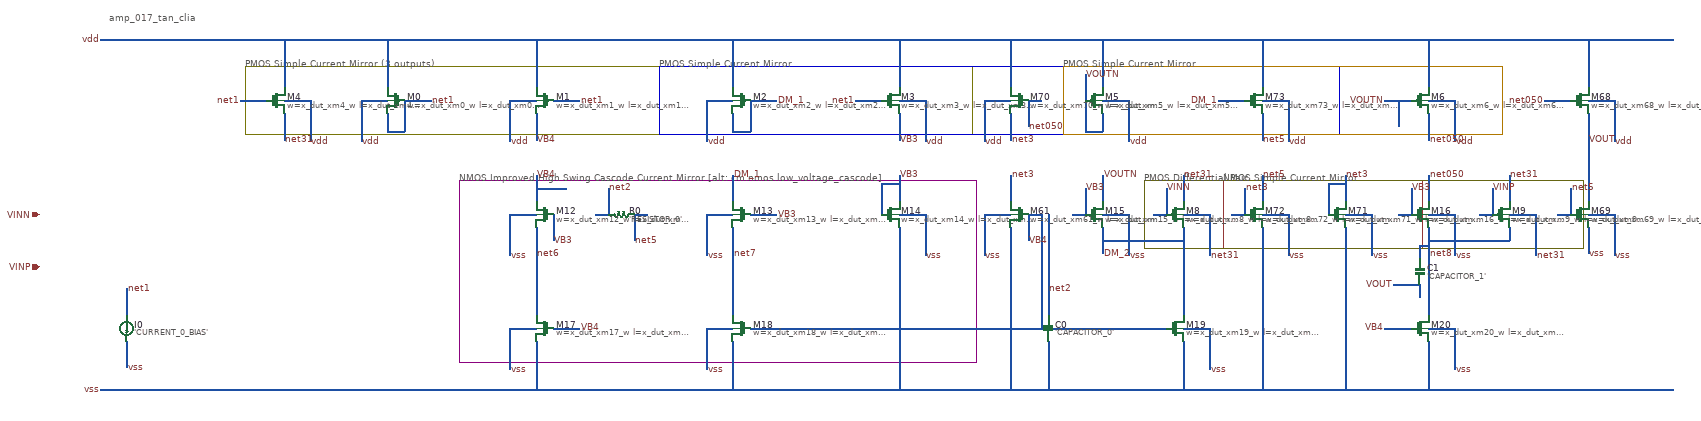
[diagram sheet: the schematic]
v {xschem version=3.4.6 file_version=1.2}
G {}
K {}
V {}
S {}
E {}
T {amp_017_tan_clia} -1755 -200 0 0 0.4 0.4 {}
C {devices/capa_np.sym} 390 520 0 0 {name=C0 value='CAPACITOR_0'}
C {devices/capa_np.sym} 1240 390 0 0 {name=C1 value='CAPACITOR_1'}
C {devices/isource_np.sym} -1715 520 0 0 {name=I0 value='CURRENT_0_BIAS'}
C {devices/res_np.sym} -585 260 1 0 {name=R0 value='RESISTOR_0'}
C {devices/sg13_lv_pmos_np.sym} -1100 0 0 1 {name=M0 model=sg13_lv_pmos spiceprefix=X w=x_dut_xm0_w l=x_dut_xm0_l m=x_dut_xm0_m}
C {devices/sg13_lv_pmos_np.sym} -760 0 0 1 {name=M1 model=sg13_lv_pmos spiceprefix=X w=x_dut_xm1_w l=x_dut_xm1_l m=x_dut_xm1_m}
C {devices/sg13_lv_nmos_np.sym} -760 260 0 1 {name=M12 model=sg13_lv_nmos spiceprefix=X w=x_dut_xm12_w l=x_dut_xm12_l m=x_dut_xm12_m}
C {devices/sg13_lv_nmos_np.sym} -310 260 0 1 {name=M13 model=sg13_lv_nmos spiceprefix=X w=x_dut_xm13_w l=x_dut_xm13_l m=x_dut_xm13_m}
C {devices/sg13_lv_nmos_np.sym} 30 260 0 0 {name=M14 model=sg13_lv_nmos spiceprefix=X w=x_dut_xm14_w l=x_dut_xm14_l m=x_dut_xm14_m}
C {devices/sg13_lv_nmos_np.sym} 495 260 0 0 {name=M15 model=sg13_lv_nmos spiceprefix=X w=x_dut_xm15_w l=x_dut_xm15_l m=x_dut_xm15_m}
C {devices/sg13_lv_nmos_np.sym} 1240 260 0 0 {name=M16 model=sg13_lv_nmos spiceprefix=X w=x_dut_xm16_w l=x_dut_xm16_l m=x_dut_xm16_m}
C {devices/sg13_lv_nmos_np.sym} -760 520 0 1 {name=M17 model=sg13_lv_nmos spiceprefix=X w=x_dut_xm17_w l=x_dut_xm17_l m=x_dut_xm17_m}
C {devices/sg13_lv_nmos_np.sym} -310 520 0 1 {name=M18 model=sg13_lv_nmos spiceprefix=X w=x_dut_xm18_w l=x_dut_xm18_l m=x_dut_xm18_m}
C {devices/sg13_lv_nmos_np.sym} 680 520 0 0 {name=M19 model=sg13_lv_nmos spiceprefix=X w=x_dut_xm19_w l=x_dut_xm19_l m=x_dut_xm19_m}
C {devices/sg13_lv_pmos_np.sym} -310 0 0 1 {name=M2 model=sg13_lv_pmos spiceprefix=X w=x_dut_xm2_w l=x_dut_xm2_l m=x_dut_xm2_m}
C {devices/sg13_lv_nmos_np.sym} 1240 520 0 0 {name=M20 model=sg13_lv_nmos spiceprefix=X w=x_dut_xm20_w l=x_dut_xm20_l m=x_dut_xm20_m}
C {devices/sg13_lv_pmos_np.sym} 30 0 0 0 {name=M3 model=sg13_lv_pmos spiceprefix=X w=x_dut_xm3_w l=x_dut_xm3_l m=x_dut_xm3_m}
C {devices/sg13_lv_pmos_np.sym} -1375 0 0 0 {name=M4 model=sg13_lv_pmos spiceprefix=X w=x_dut_xm4_w l=x_dut_xm4_l m=x_dut_xm4_m}
C {devices/sg13_lv_pmos_np.sym} 495 0 0 0 {name=M5 model=sg13_lv_pmos spiceprefix=X w=x_dut_xm5_w l=x_dut_xm5_l m=x_dut_xm5_m}
C {devices/sg13_lv_pmos_np.sym} 1240 0 0 0 {name=M6 model=sg13_lv_pmos spiceprefix=X w=x_dut_xm6_w l=x_dut_xm6_l m=x_dut_xm6_m}
C {devices/sg13_lv_nmos_np.sym} 325 260 0 1 {name=M61 model=sg13_lv_nmos spiceprefix=X w=x_dut_xm61_w l=x_dut_xm61_l m=x_dut_xm61_m}
C {devices/sg13_lv_pmos_np.sym} 1605 0 0 0 {name=M68 model=sg13_lv_pmos spiceprefix=X w=x_dut_xm68_w l=x_dut_xm68_l m=x_dut_xm68_m}
C {devices/sg13_lv_nmos_np.sym} 1605 260 0 0 {name=M69 model=sg13_lv_nmos spiceprefix=X w=x_dut_xm69_w l=x_dut_xm69_l m=x_dut_xm69_m}
C {devices/sg13_lv_pmos_np.sym} 325 0 0 1 {name=M70 model=sg13_lv_pmos spiceprefix=X w=x_dut_xm70_w l=x_dut_xm70_l m=x_dut_xm70_m}
C {devices/sg13_lv_nmos_np.sym} 1050 260 0 0 {name=M71 model=sg13_lv_nmos spiceprefix=X w=x_dut_xm71_w l=x_dut_xm71_l m=x_dut_xm71_m}
C {devices/sg13_lv_nmos_np.sym} 860 260 0 0 {name=M72 model=sg13_lv_nmos spiceprefix=X w=x_dut_xm72_w l=x_dut_xm72_l m=x_dut_xm72_m}
C {devices/sg13_lv_pmos_np.sym} 860 0 0 0 {name=M73 model=sg13_lv_pmos spiceprefix=X w=x_dut_xm73_w l=x_dut_xm73_l m=x_dut_xm73_m}
C {devices/sg13_lv_pmos_np.sym} 680 260 0 0 {name=M8 model=sg13_lv_pmos spiceprefix=X w=x_dut_xm8_w l=x_dut_xm8_l m=x_dut_xm8_m}
C {devices/sg13_lv_pmos_np.sym} 1425 260 0 0 {name=M9 model=sg13_lv_pmos spiceprefix=X w=x_dut_xm9_w l=x_dut_xm9_l m=x_dut_xm9_m}
N -1715 430 -1715 490 {}
N -1715 550 -1715 610 {}
N -1355 -140 -1355 -30 {}
N -1355 30 -1355 90 {}
N -1295 0 -1295 94 {}
N -1180 0 -1180 94 {}
N -1120 -140 -1120 -30 {}
N -1120 30 -1120 70 {}
N -1080 0 -1080 70 {}
N -840 0 -840 94 {}
N -840 260 -840 354 {}
N -840 520 -840 614 {}
N -780 -140 -780 -30 {}
N -780 30 -780 90 {}
N -780 170 -780 230 {}
N -780 290 -780 490 {}
N -780 550 -780 660 {}
N -740 260 -740 320 {}
N -615 200 -615 260 {}
N -555 260 -555 320 {}
N -390 0 -390 94 {}
N -390 260 -390 354 {}
N -390 520 -390 614 {}
N -330 -140 -330 -30 {}
N -330 30 -330 70 {}
N -330 170 -330 230 {}
N -330 290 -330 490 {}
N -330 550 -330 660 {}
N -290 0 -290 70 {}
N 10 190 10 260 {}
N 50 -140 50 -30 {}
N 50 30 50 90 {}
N 50 170 50 230 {}
N 50 290 50 660 {}
N 110 0 110 94 {}
N 110 260 110 354 {}
N 245 0 245 94 {}
N 245 260 245 354 {}
N 305 -140 305 -30 {}
N 305 30 305 90 {}
N 305 170 305 230 {}
N 305 290 305 660 {}
N 345 0 345 60 {}
N 345 260 345 320 {}
N 375 260 375 520 {}
N 390 260 390 490 {}
N 390 550 390 660 {}
N 475 -60 475 70 {}
N 475 200 475 260 {}
N 515 -140 515 -30 {}
N 515 30 515 70 {}
N 515 170 515 230 {}
N 515 290 515 350 {}
N 575 0 575 94 {}
N 575 260 575 354 {}
N 660 200 660 260 {}
N 700 170 700 230 {}
N 700 290 700 490 {}
N 700 550 700 660 {}
N 760 260 760 354 {}
N 760 520 760 614 {}
N 840 200 840 260 {}
N 880 -140 880 -30 {}
N 880 30 880 90 {}
N 880 170 880 230 {}
N 880 290 880 660 {}
N 940 0 940 94 {}
N 940 260 940 354 {}
N 1030 190 1030 260 {}
N 1070 170 1070 230 {}
N 1070 290 1070 660 {}
N 1130 260 1130 354 {}
N 1190 0 1190 60 {}
N 1220 200 1220 260 {}
N 1240 330 1240 360 {}
N 1240 420 1240 450 {}
N 1260 -140 1260 -30 {}
N 1260 30 1260 90 {}
N 1260 170 1260 230 {}
N 1260 290 1260 490 {}
N 1260 550 1260 660 {}
N 1320 0 1320 94 {}
N 1320 260 1320 354 {}
N 1320 520 1320 614 {}
N 1405 200 1405 260 {}
N 1445 170 1445 230 {}
N 1445 290 1445 320 {}
N 1505 260 1505 354 {}
N 1585 200 1585 260 {}
N 1625 -140 1625 -30 {}
N 1625 30 1625 230 {}
N 1625 290 1625 350 {}
N 1685 0 1685 94 {}
N 1685 260 1685 354 {}
N -1775 -140 1820 -140 {}
N -1455 0 -1395 0 {}
N -1355 0 -1295 0 {}
N -1180 0 -1120 0 {}
N -1080 0 -1020 0 {}
N -840 0 -780 0 {}
N -740 0 -680 0 {}
N -390 0 -330 0 {}
N -290 0 -230 0 {}
N -50 0 10 0 {}
N 50 0 110 0 {}
N 245 0 305 0 {}
N 345 0 375 0 {}
N 515 0 575 0 {}
N 780 0 840 0 {}
N 880 0 940 0 {}
N 1160 0 1220 0 {}
N 1260 0 1320 0 {}
N 1525 0 1585 0 {}
N 1625 0 1685 0 {}
N -1120 70 -1080 70 {}
N -330 70 -290 70 {}
N 475 70 515 70 {}
N 10 190 50 190 {}
N 1030 190 1070 190 {}
N -780 200 -710 200 {}
N -840 260 -780 260 {}
N -645 260 -615 260 {}
N -555 260 -525 260 {}
N -390 260 -330 260 {}
N -290 260 -230 260 {}
N 50 260 110 260 {}
N 245 260 305 260 {}
N 345 260 375 260 {}
N 445 260 475 260 {}
N 515 260 575 260 {}
N 630 260 660 260 {}
N 700 260 760 260 {}
N 810 260 840 260 {}
N 880 260 940 260 {}
N 1070 260 1130 260 {}
N 1190 260 1220 260 {}
N 1260 260 1320 260 {}
N 1375 260 1405 260 {}
N 1445 260 1505 260 {}
N 1555 260 1585 260 {}
N 1625 260 1685 260 {}
N 515 320 700 320 {}
N 1260 320 1445 320 {}
N 1240 330 1260 330 {}
N 1180 420 1240 420 {}
N -840 520 -780 520 {}
N -740 520 -680 520 {}
N -390 520 -330 520 {}
N -290 520 660 520 {}
N 700 520 760 520 {}
N 1160 520 1220 520 {}
N 1260 520 1320 520 {}
N -1775 660 1820 660 {}
C {devices/lab_wire.sym} -1775 -140 0 0 {name=l0 lab=vdd}
C {devices/lab_wire.sym} -1775 660 0 0 {name=l1 lab=vss}
C {devices/lab_wire.sym} -230 0 0 1 {name=l2 lab=DM_1}
C {devices/lab_wire.sym} -330 170 0 1 {name=l3 lab=DM_1}
C {devices/lab_wire.sym} 780 0 0 0 {name=l4 lab=DM_1}
C {devices/lab_wire.sym} 515 350 2 0 {name=l5 lab=DM_2}
C {devices/lab_wire.sym} -740 320 2 0 {name=l6 lab=VB3}
C {devices/lab_wire.sym} -230 260 0 1 {name=l7 lab=VB3}
C {devices/lab_wire.sym} 50 170 0 1 {name=l8 lab=VB3}
C {devices/lab_wire.sym} 50 90 2 0 {name=l9 lab=VB3}
C {devices/lab_wire.sym} 475 200 0 1 {name=l10 lab=VB3}
C {devices/lab_wire.sym} 1220 200 0 1 {name=l11 lab=VB3}
C {devices/lab_wire.sym} -780 90 2 0 {name=l12 lab=VB4}
C {devices/lab_wire.sym} -780 170 0 1 {name=l13 lab=VB4}
C {devices/lab_wire.sym} -680 520 0 1 {name=l14 lab=VB4}
C {devices/lab_wire.sym} 345 320 2 0 {name=l15 lab=VB4}
C {devices/lab_wire.sym} 1160 520 0 0 {name=l16 lab=VB4}
C {devices/lab_wire.sym} 660 200 0 1 {name=l17 lab=VINN}
C {devices/lab_wire.sym} 1405 200 0 1 {name=l18 lab=VINP}
C {devices/lab_wire.sym} 1180 420 0 0 {name=l19 lab=VOUT}
C {devices/lab_wire.sym} 1625 90 2 0 {name=l20 lab=VOUT}
C {devices/lab_wire.sym} 475 -60 0 1 {name=l21 lab=VOUTN}
C {devices/lab_wire.sym} 515 170 0 1 {name=l22 lab=VOUTN}
C {devices/lab_wire.sym} 1160 0 0 0 {name=l23 lab=VOUTN}
C {devices/lab_wire.sym} 345 60 2 0 {name=l24 lab=net050}
C {devices/lab_wire.sym} 1260 90 2 0 {name=l25 lab=net050}
C {devices/lab_wire.sym} 1260 170 0 1 {name=l26 lab=net050}
C {devices/lab_wire.sym} 1525 0 0 0 {name=l27 lab=net050}
C {devices/lab_wire.sym} -1455 0 0 0 {name=l28 lab=net1}
C {devices/lab_wire.sym} -1020 0 0 1 {name=l29 lab=net1}
C {devices/lab_wire.sym} -680 0 0 1 {name=l30 lab=net1}
C {devices/lab_wire.sym} -50 0 0 0 {name=l31 lab=net1}
C {devices/lab_wire.sym} -615 200 0 1 {name=l32 lab=net2}
C {devices/lab_wire.sym} 390 430 0 1 {name=l33 lab=net2}
C {devices/lab_wire.sym} 305 90 2 0 {name=l34 lab=net3}
C {devices/lab_wire.sym} 305 170 0 1 {name=l35 lab=net3}
C {devices/lab_wire.sym} 840 200 0 1 {name=l36 lab=net3}
C {devices/lab_wire.sym} 1070 170 0 1 {name=l37 lab=net3}
C {devices/lab_wire.sym} -1355 90 2 0 {name=l38 lab=net31}
C {devices/lab_wire.sym} 700 170 0 1 {name=l39 lab=net31}
C {devices/lab_wire.sym} 1445 170 0 1 {name=l40 lab=net31}
C {devices/lab_wire.sym} -555 320 2 0 {name=l41 lab=net5}
C {devices/lab_wire.sym} 880 90 2 0 {name=l42 lab=net5}
C {devices/lab_wire.sym} 880 170 0 1 {name=l43 lab=net5}
C {devices/lab_wire.sym} 1585 200 0 1 {name=l44 lab=net5}
C {devices/lab_wire.sym} -780 350 2 0 {name=l45 lab=net6}
C {devices/lab_wire.sym} -330 350 2 0 {name=l46 lab=net7}
C {devices/lab_wire.sym} 1260 350 2 0 {name=l47 lab=net8}
C {devices/lab_wire.sym} 760 354 2 0 {name=l48 lab=net31}
C {devices/lab_wire.sym} 1505 354 2 0 {name=l49 lab=net31}
C {devices/lab_wire.sym} -1180 94 2 0 {name=l50 lab=vdd}
C {devices/lab_wire.sym} -840 94 2 0 {name=l51 lab=vdd}
C {devices/lab_wire.sym} -390 94 2 0 {name=l52 lab=vdd}
C {devices/lab_wire.sym} 110 94 2 0 {name=l53 lab=vdd}
C {devices/lab_wire.sym} -1295 94 2 0 {name=l54 lab=vdd}
C {devices/lab_wire.sym} 575 94 2 0 {name=l55 lab=vdd}
C {devices/lab_wire.sym} 1320 94 2 0 {name=l56 lab=vdd}
C {devices/lab_wire.sym} 1685 94 2 0 {name=l57 lab=vdd}
C {devices/lab_wire.sym} 245 94 2 0 {name=l58 lab=vdd}
C {devices/lab_wire.sym} 940 94 2 0 {name=l59 lab=vdd}
C {devices/lab_wire.sym} -840 354 2 0 {name=l60 lab=vss}
C {devices/lab_wire.sym} -390 354 2 0 {name=l61 lab=vss}
C {devices/lab_wire.sym} 110 354 2 0 {name=l62 lab=vss}
C {devices/lab_wire.sym} 575 354 2 0 {name=l63 lab=vss}
C {devices/lab_wire.sym} 1320 354 2 0 {name=l64 lab=vss}
C {devices/lab_wire.sym} -840 614 2 0 {name=l65 lab=vss}
C {devices/lab_wire.sym} -390 614 2 0 {name=l66 lab=vss}
C {devices/lab_wire.sym} 760 614 2 0 {name=l67 lab=vss}
C {devices/lab_wire.sym} 1320 614 2 0 {name=l68 lab=vss}
C {devices/lab_wire.sym} 245 354 2 0 {name=l69 lab=vss}
C {devices/lab_wire.sym} 1685 354 2 0 {name=l70 lab=vss}
C {devices/lab_wire.sym} 1130 354 2 0 {name=l71 lab=vss}
C {devices/lab_wire.sym} 940 354 2 0 {name=l72 lab=vss}
C {devices/lab_wire.sym} -1715 610 2 0 {name=l73 lab=vss}
C {devices/lab_wire.sym} -1715 430 0 1 {name=l74 lab=net1}
C {devices/lab_wire.sym} 1625 350 2 0 {name=l75 lab=vss}
C {devices/ipin.sym} -1915 260 0 0 {name=p0 lab=VINN}
C {devices/ipin.sym} -1915 380 0 0 {name=p1 lab=VINP}
B 8 -1445 -78 218 78 {fill=0}
T {PMOS Simple Current Mirror (3 outputs)} -1445 -96 0 0 0.3 0.3 {layer=8}
B 10 -956 182 226 598 {fill=0}
T {NMOS Improved High Swing Cascode Current Mirror [alt: cm.nmos.low_voltage_cascode]} -956 164 0 0 0.3 0.3 {layer=10}
B 12 -498 -78 1056 78 {fill=0}
T {PMOS Simple Current Mirror} -498 -96 0 0 0.3 0.3 {layer=12}
B 21 425 -78 1428 78 {fill=0}
T {PMOS Simple Current Mirror} 425 -96 0 0 0.3 0.3 {layer=21}
B 15 790 182 1246 338 {fill=0}
T {NMOS Simple Current Mirror} 790 164 0 0 0.3 0.3 {layer=15}
B 13 610 182 1613 338 {fill=0}
T {PMOS Differential Pair} 610 164 0 0 0.3 0.3 {layer=13}
